VERSION 5.7 ;
BUSBITCHARS "[]" ;
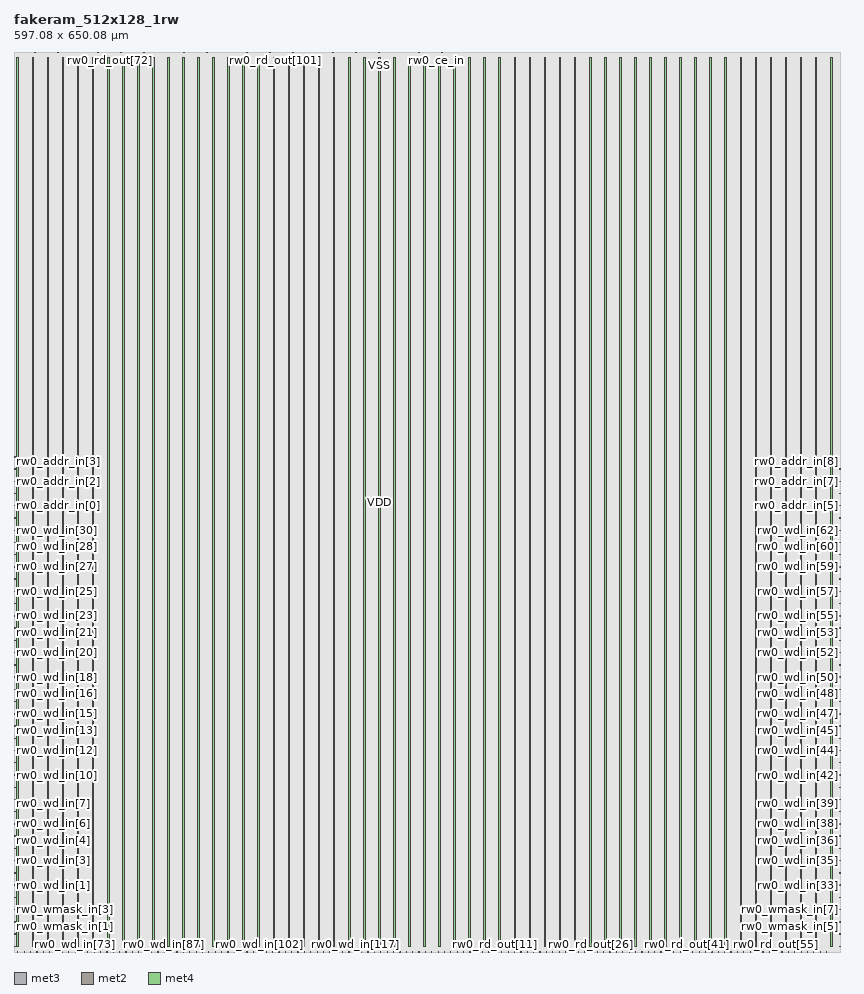
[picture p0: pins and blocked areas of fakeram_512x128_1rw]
MACRO fakeram_512x128_1rw
  FOREIGN fakeram_512x128_1rw 0 0 ;
  SYMMETRY X Y R90 ;
  SIZE 597.080 BY 650.080 ;
  CLASS BLOCK ;
  PIN rw0_wmask_in[0]
    DIRECTION INPUT ;
    USE SIGNAL ;
    SHAPE ABUTMENT ;
    PORT
      LAYER met3 ;
      RECT 0.000 3.930 0.900 4.230 ;
    END
  END rw0_wmask_in[0]
  PIN rw0_wmask_in[1]
    DIRECTION INPUT ;
    USE SIGNAL ;
    SHAPE ABUTMENT ;
    PORT
      LAYER met3 ;
      RECT 0.000 12.770 0.900 13.070 ;
    END
  END rw0_wmask_in[1]
  PIN rw0_wmask_in[2]
    DIRECTION INPUT ;
    USE SIGNAL ;
    SHAPE ABUTMENT ;
    PORT
      LAYER met3 ;
      RECT 0.000 21.610 0.900 21.910 ;
    END
  END rw0_wmask_in[2]
  PIN rw0_wmask_in[3]
    DIRECTION INPUT ;
    USE SIGNAL ;
    SHAPE ABUTMENT ;
    PORT
      LAYER met3 ;
      RECT 0.000 30.450 0.900 30.750 ;
    END
  END rw0_wmask_in[3]
  PIN rw0_wmask_in[4]
    DIRECTION INPUT ;
    USE SIGNAL ;
    SHAPE ABUTMENT ;
    PORT
      LAYER met3 ;
      RECT 596.180 3.930 597.080 4.230 ;
    END
  END rw0_wmask_in[4]
  PIN rw0_wmask_in[5]
    DIRECTION INPUT ;
    USE SIGNAL ;
    SHAPE ABUTMENT ;
    PORT
      LAYER met3 ;
      RECT 596.180 12.770 597.080 13.070 ;
    END
  END rw0_wmask_in[5]
  PIN rw0_wmask_in[6]
    DIRECTION INPUT ;
    USE SIGNAL ;
    SHAPE ABUTMENT ;
    PORT
      LAYER met3 ;
      RECT 596.180 21.610 597.080 21.910 ;
    END
  END rw0_wmask_in[6]
  PIN rw0_wmask_in[7]
    DIRECTION INPUT ;
    USE SIGNAL ;
    SHAPE ABUTMENT ;
    PORT
      LAYER met3 ;
      RECT 596.180 30.450 597.080 30.750 ;
    END
  END rw0_wmask_in[7]
  PIN rw0_wmask_in[8]
    DIRECTION INPUT ;
    USE SIGNAL ;
    SHAPE ABUTMENT ;
    PORT
      LAYER met2 ;
      RECT 2.690 649.660 2.830 650.080 ;
    END
  END rw0_wmask_in[8]
  PIN rw0_wmask_in[9]
    DIRECTION INPUT ;
    USE SIGNAL ;
    SHAPE ABUTMENT ;
    PORT
      LAYER met2 ;
      RECT 6.830 649.660 6.970 650.080 ;
    END
  END rw0_wmask_in[9]
  PIN rw0_wmask_in[10]
    DIRECTION INPUT ;
    USE SIGNAL ;
    SHAPE ABUTMENT ;
    PORT
      LAYER met2 ;
      RECT 10.970 649.660 11.110 650.080 ;
    END
  END rw0_wmask_in[10]
  PIN rw0_wmask_in[11]
    DIRECTION INPUT ;
    USE SIGNAL ;
    SHAPE ABUTMENT ;
    PORT
      LAYER met2 ;
      RECT 15.110 649.660 15.250 650.080 ;
    END
  END rw0_wmask_in[11]
  PIN rw0_wmask_in[12]
    DIRECTION INPUT ;
    USE SIGNAL ;
    SHAPE ABUTMENT ;
    PORT
      LAYER met2 ;
      RECT 19.250 649.660 19.390 650.080 ;
    END
  END rw0_wmask_in[12]
  PIN rw0_wmask_in[13]
    DIRECTION INPUT ;
    USE SIGNAL ;
    SHAPE ABUTMENT ;
    PORT
      LAYER met2 ;
      RECT 23.390 649.660 23.530 650.080 ;
    END
  END rw0_wmask_in[13]
  PIN rw0_wmask_in[14]
    DIRECTION INPUT ;
    USE SIGNAL ;
    SHAPE ABUTMENT ;
    PORT
      LAYER met2 ;
      RECT 27.530 649.660 27.670 650.080 ;
    END
  END rw0_wmask_in[14]
  PIN rw0_wmask_in[15]
    DIRECTION INPUT ;
    USE SIGNAL ;
    SHAPE ABUTMENT ;
    PORT
      LAYER met2 ;
      RECT 31.670 649.660 31.810 650.080 ;
    END
  END rw0_wmask_in[15]
  PIN rw0_wd_in[0]
    DIRECTION INPUT ;
    USE SIGNAL ;
    SHAPE ABUTMENT ;
    PORT
      LAYER met3 ;
      RECT 0.000 39.290 0.900 39.590 ;
    END
  END rw0_wd_in[0]
  PIN rw0_wd_in[1]
    DIRECTION INPUT ;
    USE SIGNAL ;
    SHAPE ABUTMENT ;
    PORT
      LAYER met3 ;
      RECT 0.000 48.130 0.900 48.430 ;
    END
  END rw0_wd_in[1]
  PIN rw0_wd_in[2]
    DIRECTION INPUT ;
    USE SIGNAL ;
    SHAPE ABUTMENT ;
    PORT
      LAYER met3 ;
      RECT 0.000 56.970 0.900 57.270 ;
    END
  END rw0_wd_in[2]
  PIN rw0_wd_in[3]
    DIRECTION INPUT ;
    USE SIGNAL ;
    SHAPE ABUTMENT ;
    PORT
      LAYER met3 ;
      RECT 0.000 65.810 0.900 66.110 ;
    END
  END rw0_wd_in[3]
  PIN rw0_wd_in[4]
    DIRECTION INPUT ;
    USE SIGNAL ;
    SHAPE ABUTMENT ;
    PORT
      LAYER met3 ;
      RECT 0.000 74.650 0.900 74.950 ;
    END
  END rw0_wd_in[4]
  PIN rw0_wd_in[5]
    DIRECTION INPUT ;
    USE SIGNAL ;
    SHAPE ABUTMENT ;
    PORT
      LAYER met3 ;
      RECT 0.000 83.490 0.900 83.790 ;
    END
  END rw0_wd_in[5]
  PIN rw0_wd_in[6]
    DIRECTION INPUT ;
    USE SIGNAL ;
    SHAPE ABUTMENT ;
    PORT
      LAYER met3 ;
      RECT 0.000 92.330 0.900 92.630 ;
    END
  END rw0_wd_in[6]
  PIN rw0_wd_in[7]
    DIRECTION INPUT ;
    USE SIGNAL ;
    SHAPE ABUTMENT ;
    PORT
      LAYER met3 ;
      RECT 0.000 101.170 0.900 101.470 ;
    END
  END rw0_wd_in[7]
  PIN rw0_wd_in[8]
    DIRECTION INPUT ;
    USE SIGNAL ;
    SHAPE ABUTMENT ;
    PORT
      LAYER met3 ;
      RECT 0.000 110.010 0.900 110.310 ;
    END
  END rw0_wd_in[8]
  PIN rw0_wd_in[9]
    DIRECTION INPUT ;
    USE SIGNAL ;
    SHAPE ABUTMENT ;
    PORT
      LAYER met3 ;
      RECT 0.000 118.850 0.900 119.150 ;
    END
  END rw0_wd_in[9]
  PIN rw0_wd_in[10]
    DIRECTION INPUT ;
    USE SIGNAL ;
    SHAPE ABUTMENT ;
    PORT
      LAYER met3 ;
      RECT 0.000 127.690 0.900 127.990 ;
    END
  END rw0_wd_in[10]
  PIN rw0_wd_in[11]
    DIRECTION INPUT ;
    USE SIGNAL ;
    SHAPE ABUTMENT ;
    PORT
      LAYER met3 ;
      RECT 0.000 136.530 0.900 136.830 ;
    END
  END rw0_wd_in[11]
  PIN rw0_wd_in[12]
    DIRECTION INPUT ;
    USE SIGNAL ;
    SHAPE ABUTMENT ;
    PORT
      LAYER met3 ;
      RECT 0.000 145.370 0.900 145.670 ;
    END
  END rw0_wd_in[12]
  PIN rw0_wd_in[13]
    DIRECTION INPUT ;
    USE SIGNAL ;
    SHAPE ABUTMENT ;
    PORT
      LAYER met3 ;
      RECT 0.000 154.210 0.900 154.510 ;
    END
  END rw0_wd_in[13]
  PIN rw0_wd_in[14]
    DIRECTION INPUT ;
    USE SIGNAL ;
    SHAPE ABUTMENT ;
    PORT
      LAYER met3 ;
      RECT 0.000 163.050 0.900 163.350 ;
    END
  END rw0_wd_in[14]
  PIN rw0_wd_in[15]
    DIRECTION INPUT ;
    USE SIGNAL ;
    SHAPE ABUTMENT ;
    PORT
      LAYER met3 ;
      RECT 0.000 171.890 0.900 172.190 ;
    END
  END rw0_wd_in[15]
  PIN rw0_wd_in[16]
    DIRECTION INPUT ;
    USE SIGNAL ;
    SHAPE ABUTMENT ;
    PORT
      LAYER met3 ;
      RECT 0.000 180.730 0.900 181.030 ;
    END
  END rw0_wd_in[16]
  PIN rw0_wd_in[17]
    DIRECTION INPUT ;
    USE SIGNAL ;
    SHAPE ABUTMENT ;
    PORT
      LAYER met3 ;
      RECT 0.000 189.570 0.900 189.870 ;
    END
  END rw0_wd_in[17]
  PIN rw0_wd_in[18]
    DIRECTION INPUT ;
    USE SIGNAL ;
    SHAPE ABUTMENT ;
    PORT
      LAYER met3 ;
      RECT 0.000 198.410 0.900 198.710 ;
    END
  END rw0_wd_in[18]
  PIN rw0_wd_in[19]
    DIRECTION INPUT ;
    USE SIGNAL ;
    SHAPE ABUTMENT ;
    PORT
      LAYER met3 ;
      RECT 0.000 207.250 0.900 207.550 ;
    END
  END rw0_wd_in[19]
  PIN rw0_wd_in[20]
    DIRECTION INPUT ;
    USE SIGNAL ;
    SHAPE ABUTMENT ;
    PORT
      LAYER met3 ;
      RECT 0.000 216.090 0.900 216.390 ;
    END
  END rw0_wd_in[20]
  PIN rw0_wd_in[21]
    DIRECTION INPUT ;
    USE SIGNAL ;
    SHAPE ABUTMENT ;
    PORT
      LAYER met3 ;
      RECT 0.000 224.930 0.900 225.230 ;
    END
  END rw0_wd_in[21]
  PIN rw0_wd_in[22]
    DIRECTION INPUT ;
    USE SIGNAL ;
    SHAPE ABUTMENT ;
    PORT
      LAYER met3 ;
      RECT 0.000 233.770 0.900 234.070 ;
    END
  END rw0_wd_in[22]
  PIN rw0_wd_in[23]
    DIRECTION INPUT ;
    USE SIGNAL ;
    SHAPE ABUTMENT ;
    PORT
      LAYER met3 ;
      RECT 0.000 242.610 0.900 242.910 ;
    END
  END rw0_wd_in[23]
  PIN rw0_wd_in[24]
    DIRECTION INPUT ;
    USE SIGNAL ;
    SHAPE ABUTMENT ;
    PORT
      LAYER met3 ;
      RECT 0.000 251.450 0.900 251.750 ;
    END
  END rw0_wd_in[24]
  PIN rw0_wd_in[25]
    DIRECTION INPUT ;
    USE SIGNAL ;
    SHAPE ABUTMENT ;
    PORT
      LAYER met3 ;
      RECT 0.000 260.290 0.900 260.590 ;
    END
  END rw0_wd_in[25]
  PIN rw0_wd_in[26]
    DIRECTION INPUT ;
    USE SIGNAL ;
    SHAPE ABUTMENT ;
    PORT
      LAYER met3 ;
      RECT 0.000 269.130 0.900 269.430 ;
    END
  END rw0_wd_in[26]
  PIN rw0_wd_in[27]
    DIRECTION INPUT ;
    USE SIGNAL ;
    SHAPE ABUTMENT ;
    PORT
      LAYER met3 ;
      RECT 0.000 277.970 0.900 278.270 ;
    END
  END rw0_wd_in[27]
  PIN rw0_wd_in[28]
    DIRECTION INPUT ;
    USE SIGNAL ;
    SHAPE ABUTMENT ;
    PORT
      LAYER met3 ;
      RECT 0.000 286.810 0.900 287.110 ;
    END
  END rw0_wd_in[28]
  PIN rw0_wd_in[29]
    DIRECTION INPUT ;
    USE SIGNAL ;
    SHAPE ABUTMENT ;
    PORT
      LAYER met3 ;
      RECT 0.000 295.650 0.900 295.950 ;
    END
  END rw0_wd_in[29]
  PIN rw0_wd_in[30]
    DIRECTION INPUT ;
    USE SIGNAL ;
    SHAPE ABUTMENT ;
    PORT
      LAYER met3 ;
      RECT 0.000 304.490 0.900 304.790 ;
    END
  END rw0_wd_in[30]
  PIN rw0_wd_in[31]
    DIRECTION INPUT ;
    USE SIGNAL ;
    SHAPE ABUTMENT ;
    PORT
      LAYER met3 ;
      RECT 0.000 313.330 0.900 313.630 ;
    END
  END rw0_wd_in[31]
  PIN rw0_wd_in[32]
    DIRECTION INPUT ;
    USE SIGNAL ;
    SHAPE ABUTMENT ;
    PORT
      LAYER met3 ;
      RECT 596.180 39.290 597.080 39.590 ;
    END
  END rw0_wd_in[32]
  PIN rw0_wd_in[33]
    DIRECTION INPUT ;
    USE SIGNAL ;
    SHAPE ABUTMENT ;
    PORT
      LAYER met3 ;
      RECT 596.180 48.130 597.080 48.430 ;
    END
  END rw0_wd_in[33]
  PIN rw0_wd_in[34]
    DIRECTION INPUT ;
    USE SIGNAL ;
    SHAPE ABUTMENT ;
    PORT
      LAYER met3 ;
      RECT 596.180 56.970 597.080 57.270 ;
    END
  END rw0_wd_in[34]
  PIN rw0_wd_in[35]
    DIRECTION INPUT ;
    USE SIGNAL ;
    SHAPE ABUTMENT ;
    PORT
      LAYER met3 ;
      RECT 596.180 65.810 597.080 66.110 ;
    END
  END rw0_wd_in[35]
  PIN rw0_wd_in[36]
    DIRECTION INPUT ;
    USE SIGNAL ;
    SHAPE ABUTMENT ;
    PORT
      LAYER met3 ;
      RECT 596.180 74.650 597.080 74.950 ;
    END
  END rw0_wd_in[36]
  PIN rw0_wd_in[37]
    DIRECTION INPUT ;
    USE SIGNAL ;
    SHAPE ABUTMENT ;
    PORT
      LAYER met3 ;
      RECT 596.180 83.490 597.080 83.790 ;
    END
  END rw0_wd_in[37]
  PIN rw0_wd_in[38]
    DIRECTION INPUT ;
    USE SIGNAL ;
    SHAPE ABUTMENT ;
    PORT
      LAYER met3 ;
      RECT 596.180 92.330 597.080 92.630 ;
    END
  END rw0_wd_in[38]
  PIN rw0_wd_in[39]
    DIRECTION INPUT ;
    USE SIGNAL ;
    SHAPE ABUTMENT ;
    PORT
      LAYER met3 ;
      RECT 596.180 101.170 597.080 101.470 ;
    END
  END rw0_wd_in[39]
  PIN rw0_wd_in[40]
    DIRECTION INPUT ;
    USE SIGNAL ;
    SHAPE ABUTMENT ;
    PORT
      LAYER met3 ;
      RECT 596.180 110.010 597.080 110.310 ;
    END
  END rw0_wd_in[40]
  PIN rw0_wd_in[41]
    DIRECTION INPUT ;
    USE SIGNAL ;
    SHAPE ABUTMENT ;
    PORT
      LAYER met3 ;
      RECT 596.180 118.850 597.080 119.150 ;
    END
  END rw0_wd_in[41]
  PIN rw0_wd_in[42]
    DIRECTION INPUT ;
    USE SIGNAL ;
    SHAPE ABUTMENT ;
    PORT
      LAYER met3 ;
      RECT 596.180 127.690 597.080 127.990 ;
    END
  END rw0_wd_in[42]
  PIN rw0_wd_in[43]
    DIRECTION INPUT ;
    USE SIGNAL ;
    SHAPE ABUTMENT ;
    PORT
      LAYER met3 ;
      RECT 596.180 136.530 597.080 136.830 ;
    END
  END rw0_wd_in[43]
  PIN rw0_wd_in[44]
    DIRECTION INPUT ;
    USE SIGNAL ;
    SHAPE ABUTMENT ;
    PORT
      LAYER met3 ;
      RECT 596.180 145.370 597.080 145.670 ;
    END
  END rw0_wd_in[44]
  PIN rw0_wd_in[45]
    DIRECTION INPUT ;
    USE SIGNAL ;
    SHAPE ABUTMENT ;
    PORT
      LAYER met3 ;
      RECT 596.180 154.210 597.080 154.510 ;
    END
  END rw0_wd_in[45]
  PIN rw0_wd_in[46]
    DIRECTION INPUT ;
    USE SIGNAL ;
    SHAPE ABUTMENT ;
    PORT
      LAYER met3 ;
      RECT 596.180 163.050 597.080 163.350 ;
    END
  END rw0_wd_in[46]
  PIN rw0_wd_in[47]
    DIRECTION INPUT ;
    USE SIGNAL ;
    SHAPE ABUTMENT ;
    PORT
      LAYER met3 ;
      RECT 596.180 171.890 597.080 172.190 ;
    END
  END rw0_wd_in[47]
  PIN rw0_wd_in[48]
    DIRECTION INPUT ;
    USE SIGNAL ;
    SHAPE ABUTMENT ;
    PORT
      LAYER met3 ;
      RECT 596.180 180.730 597.080 181.030 ;
    END
  END rw0_wd_in[48]
  PIN rw0_wd_in[49]
    DIRECTION INPUT ;
    USE SIGNAL ;
    SHAPE ABUTMENT ;
    PORT
      LAYER met3 ;
      RECT 596.180 189.570 597.080 189.870 ;
    END
  END rw0_wd_in[49]
  PIN rw0_wd_in[50]
    DIRECTION INPUT ;
    USE SIGNAL ;
    SHAPE ABUTMENT ;
    PORT
      LAYER met3 ;
      RECT 596.180 198.410 597.080 198.710 ;
    END
  END rw0_wd_in[50]
  PIN rw0_wd_in[51]
    DIRECTION INPUT ;
    USE SIGNAL ;
    SHAPE ABUTMENT ;
    PORT
      LAYER met3 ;
      RECT 596.180 207.250 597.080 207.550 ;
    END
  END rw0_wd_in[51]
  PIN rw0_wd_in[52]
    DIRECTION INPUT ;
    USE SIGNAL ;
    SHAPE ABUTMENT ;
    PORT
      LAYER met3 ;
      RECT 596.180 216.090 597.080 216.390 ;
    END
  END rw0_wd_in[52]
  PIN rw0_wd_in[53]
    DIRECTION INPUT ;
    USE SIGNAL ;
    SHAPE ABUTMENT ;
    PORT
      LAYER met3 ;
      RECT 596.180 224.930 597.080 225.230 ;
    END
  END rw0_wd_in[53]
  PIN rw0_wd_in[54]
    DIRECTION INPUT ;
    USE SIGNAL ;
    SHAPE ABUTMENT ;
    PORT
      LAYER met3 ;
      RECT 596.180 233.770 597.080 234.070 ;
    END
  END rw0_wd_in[54]
  PIN rw0_wd_in[55]
    DIRECTION INPUT ;
    USE SIGNAL ;
    SHAPE ABUTMENT ;
    PORT
      LAYER met3 ;
      RECT 596.180 242.610 597.080 242.910 ;
    END
  END rw0_wd_in[55]
  PIN rw0_wd_in[56]
    DIRECTION INPUT ;
    USE SIGNAL ;
    SHAPE ABUTMENT ;
    PORT
      LAYER met3 ;
      RECT 596.180 251.450 597.080 251.750 ;
    END
  END rw0_wd_in[56]
  PIN rw0_wd_in[57]
    DIRECTION INPUT ;
    USE SIGNAL ;
    SHAPE ABUTMENT ;
    PORT
      LAYER met3 ;
      RECT 596.180 260.290 597.080 260.590 ;
    END
  END rw0_wd_in[57]
  PIN rw0_wd_in[58]
    DIRECTION INPUT ;
    USE SIGNAL ;
    SHAPE ABUTMENT ;
    PORT
      LAYER met3 ;
      RECT 596.180 269.130 597.080 269.430 ;
    END
  END rw0_wd_in[58]
  PIN rw0_wd_in[59]
    DIRECTION INPUT ;
    USE SIGNAL ;
    SHAPE ABUTMENT ;
    PORT
      LAYER met3 ;
      RECT 596.180 277.970 597.080 278.270 ;
    END
  END rw0_wd_in[59]
  PIN rw0_wd_in[60]
    DIRECTION INPUT ;
    USE SIGNAL ;
    SHAPE ABUTMENT ;
    PORT
      LAYER met3 ;
      RECT 596.180 286.810 597.080 287.110 ;
    END
  END rw0_wd_in[60]
  PIN rw0_wd_in[61]
    DIRECTION INPUT ;
    USE SIGNAL ;
    SHAPE ABUTMENT ;
    PORT
      LAYER met3 ;
      RECT 596.180 295.650 597.080 295.950 ;
    END
  END rw0_wd_in[61]
  PIN rw0_wd_in[62]
    DIRECTION INPUT ;
    USE SIGNAL ;
    SHAPE ABUTMENT ;
    PORT
      LAYER met3 ;
      RECT 596.180 304.490 597.080 304.790 ;
    END
  END rw0_wd_in[62]
  PIN rw0_wd_in[63]
    DIRECTION INPUT ;
    USE SIGNAL ;
    SHAPE ABUTMENT ;
    PORT
      LAYER met3 ;
      RECT 596.180 313.330 597.080 313.630 ;
    END
  END rw0_wd_in[63]
  PIN rw0_wd_in[64]
    DIRECTION OUTPUT ;
    USE SIGNAL ;
    SHAPE ABUTMENT ;
    PORT
      LAYER met2 ;
      RECT 2.690 0.000 2.830 0.420 ;
    END
  END rw0_wd_in[64]
  PIN rw0_wd_in[65]
    DIRECTION OUTPUT ;
    USE SIGNAL ;
    SHAPE ABUTMENT ;
    PORT
      LAYER met2 ;
      RECT 7.290 0.000 7.430 0.420 ;
    END
  END rw0_wd_in[65]
  PIN rw0_wd_in[66]
    DIRECTION OUTPUT ;
    USE SIGNAL ;
    SHAPE ABUTMENT ;
    PORT
      LAYER met2 ;
      RECT 11.890 0.000 12.030 0.420 ;
    END
  END rw0_wd_in[66]
  PIN rw0_wd_in[67]
    DIRECTION OUTPUT ;
    USE SIGNAL ;
    SHAPE ABUTMENT ;
    PORT
      LAYER met2 ;
      RECT 16.490 0.000 16.630 0.420 ;
    END
  END rw0_wd_in[67]
  PIN rw0_wd_in[68]
    DIRECTION OUTPUT ;
    USE SIGNAL ;
    SHAPE ABUTMENT ;
    PORT
      LAYER met2 ;
      RECT 21.090 0.000 21.230 0.420 ;
    END
  END rw0_wd_in[68]
  PIN rw0_wd_in[69]
    DIRECTION OUTPUT ;
    USE SIGNAL ;
    SHAPE ABUTMENT ;
    PORT
      LAYER met2 ;
      RECT 25.690 0.000 25.830 0.420 ;
    END
  END rw0_wd_in[69]
  PIN rw0_wd_in[70]
    DIRECTION OUTPUT ;
    USE SIGNAL ;
    SHAPE ABUTMENT ;
    PORT
      LAYER met2 ;
      RECT 30.290 0.000 30.430 0.420 ;
    END
  END rw0_wd_in[70]
  PIN rw0_wd_in[71]
    DIRECTION OUTPUT ;
    USE SIGNAL ;
    SHAPE ABUTMENT ;
    PORT
      LAYER met2 ;
      RECT 34.890 0.000 35.030 0.420 ;
    END
  END rw0_wd_in[71]
  PIN rw0_wd_in[72]
    DIRECTION OUTPUT ;
    USE SIGNAL ;
    SHAPE ABUTMENT ;
    PORT
      LAYER met2 ;
      RECT 39.490 0.000 39.630 0.420 ;
    END
  END rw0_wd_in[72]
  PIN rw0_wd_in[73]
    DIRECTION OUTPUT ;
    USE SIGNAL ;
    SHAPE ABUTMENT ;
    PORT
      LAYER met2 ;
      RECT 44.090 0.000 44.230 0.420 ;
    END
  END rw0_wd_in[73]
  PIN rw0_wd_in[74]
    DIRECTION OUTPUT ;
    USE SIGNAL ;
    SHAPE ABUTMENT ;
    PORT
      LAYER met2 ;
      RECT 48.690 0.000 48.830 0.420 ;
    END
  END rw0_wd_in[74]
  PIN rw0_wd_in[75]
    DIRECTION OUTPUT ;
    USE SIGNAL ;
    SHAPE ABUTMENT ;
    PORT
      LAYER met2 ;
      RECT 53.290 0.000 53.430 0.420 ;
    END
  END rw0_wd_in[75]
  PIN rw0_wd_in[76]
    DIRECTION OUTPUT ;
    USE SIGNAL ;
    SHAPE ABUTMENT ;
    PORT
      LAYER met2 ;
      RECT 57.890 0.000 58.030 0.420 ;
    END
  END rw0_wd_in[76]
  PIN rw0_wd_in[77]
    DIRECTION OUTPUT ;
    USE SIGNAL ;
    SHAPE ABUTMENT ;
    PORT
      LAYER met2 ;
      RECT 62.490 0.000 62.630 0.420 ;
    END
  END rw0_wd_in[77]
  PIN rw0_wd_in[78]
    DIRECTION OUTPUT ;
    USE SIGNAL ;
    SHAPE ABUTMENT ;
    PORT
      LAYER met2 ;
      RECT 67.090 0.000 67.230 0.420 ;
    END
  END rw0_wd_in[78]
  PIN rw0_wd_in[79]
    DIRECTION OUTPUT ;
    USE SIGNAL ;
    SHAPE ABUTMENT ;
    PORT
      LAYER met2 ;
      RECT 71.690 0.000 71.830 0.420 ;
    END
  END rw0_wd_in[79]
  PIN rw0_wd_in[80]
    DIRECTION OUTPUT ;
    USE SIGNAL ;
    SHAPE ABUTMENT ;
    PORT
      LAYER met2 ;
      RECT 76.290 0.000 76.430 0.420 ;
    END
  END rw0_wd_in[80]
  PIN rw0_wd_in[81]
    DIRECTION OUTPUT ;
    USE SIGNAL ;
    SHAPE ABUTMENT ;
    PORT
      LAYER met2 ;
      RECT 80.890 0.000 81.030 0.420 ;
    END
  END rw0_wd_in[81]
  PIN rw0_wd_in[82]
    DIRECTION OUTPUT ;
    USE SIGNAL ;
    SHAPE ABUTMENT ;
    PORT
      LAYER met2 ;
      RECT 85.490 0.000 85.630 0.420 ;
    END
  END rw0_wd_in[82]
  PIN rw0_wd_in[83]
    DIRECTION OUTPUT ;
    USE SIGNAL ;
    SHAPE ABUTMENT ;
    PORT
      LAYER met2 ;
      RECT 90.090 0.000 90.230 0.420 ;
    END
  END rw0_wd_in[83]
  PIN rw0_wd_in[84]
    DIRECTION OUTPUT ;
    USE SIGNAL ;
    SHAPE ABUTMENT ;
    PORT
      LAYER met2 ;
      RECT 94.690 0.000 94.830 0.420 ;
    END
  END rw0_wd_in[84]
  PIN rw0_wd_in[85]
    DIRECTION OUTPUT ;
    USE SIGNAL ;
    SHAPE ABUTMENT ;
    PORT
      LAYER met2 ;
      RECT 99.290 0.000 99.430 0.420 ;
    END
  END rw0_wd_in[85]
  PIN rw0_wd_in[86]
    DIRECTION OUTPUT ;
    USE SIGNAL ;
    SHAPE ABUTMENT ;
    PORT
      LAYER met2 ;
      RECT 103.890 0.000 104.030 0.420 ;
    END
  END rw0_wd_in[86]
  PIN rw0_wd_in[87]
    DIRECTION OUTPUT ;
    USE SIGNAL ;
    SHAPE ABUTMENT ;
    PORT
      LAYER met2 ;
      RECT 108.490 0.000 108.630 0.420 ;
    END
  END rw0_wd_in[87]
  PIN rw0_wd_in[88]
    DIRECTION OUTPUT ;
    USE SIGNAL ;
    SHAPE ABUTMENT ;
    PORT
      LAYER met2 ;
      RECT 113.090 0.000 113.230 0.420 ;
    END
  END rw0_wd_in[88]
  PIN rw0_wd_in[89]
    DIRECTION OUTPUT ;
    USE SIGNAL ;
    SHAPE ABUTMENT ;
    PORT
      LAYER met2 ;
      RECT 117.690 0.000 117.830 0.420 ;
    END
  END rw0_wd_in[89]
  PIN rw0_wd_in[90]
    DIRECTION OUTPUT ;
    USE SIGNAL ;
    SHAPE ABUTMENT ;
    PORT
      LAYER met2 ;
      RECT 122.290 0.000 122.430 0.420 ;
    END
  END rw0_wd_in[90]
  PIN rw0_wd_in[91]
    DIRECTION OUTPUT ;
    USE SIGNAL ;
    SHAPE ABUTMENT ;
    PORT
      LAYER met2 ;
      RECT 126.890 0.000 127.030 0.420 ;
    END
  END rw0_wd_in[91]
  PIN rw0_wd_in[92]
    DIRECTION OUTPUT ;
    USE SIGNAL ;
    SHAPE ABUTMENT ;
    PORT
      LAYER met2 ;
      RECT 131.490 0.000 131.630 0.420 ;
    END
  END rw0_wd_in[92]
  PIN rw0_wd_in[93]
    DIRECTION OUTPUT ;
    USE SIGNAL ;
    SHAPE ABUTMENT ;
    PORT
      LAYER met2 ;
      RECT 136.090 0.000 136.230 0.420 ;
    END
  END rw0_wd_in[93]
  PIN rw0_wd_in[94]
    DIRECTION OUTPUT ;
    USE SIGNAL ;
    SHAPE ABUTMENT ;
    PORT
      LAYER met2 ;
      RECT 140.690 0.000 140.830 0.420 ;
    END
  END rw0_wd_in[94]
  PIN rw0_wd_in[95]
    DIRECTION OUTPUT ;
    USE SIGNAL ;
    SHAPE ABUTMENT ;
    PORT
      LAYER met2 ;
      RECT 145.290 0.000 145.430 0.420 ;
    END
  END rw0_wd_in[95]
  PIN rw0_wd_in[96]
    DIRECTION OUTPUT ;
    USE SIGNAL ;
    SHAPE ABUTMENT ;
    PORT
      LAYER met2 ;
      RECT 149.890 0.000 150.030 0.420 ;
    END
  END rw0_wd_in[96]
  PIN rw0_wd_in[97]
    DIRECTION OUTPUT ;
    USE SIGNAL ;
    SHAPE ABUTMENT ;
    PORT
      LAYER met2 ;
      RECT 154.490 0.000 154.630 0.420 ;
    END
  END rw0_wd_in[97]
  PIN rw0_wd_in[98]
    DIRECTION OUTPUT ;
    USE SIGNAL ;
    SHAPE ABUTMENT ;
    PORT
      LAYER met2 ;
      RECT 159.090 0.000 159.230 0.420 ;
    END
  END rw0_wd_in[98]
  PIN rw0_wd_in[99]
    DIRECTION OUTPUT ;
    USE SIGNAL ;
    SHAPE ABUTMENT ;
    PORT
      LAYER met2 ;
      RECT 163.690 0.000 163.830 0.420 ;
    END
  END rw0_wd_in[99]
  PIN rw0_wd_in[100]
    DIRECTION OUTPUT ;
    USE SIGNAL ;
    SHAPE ABUTMENT ;
    PORT
      LAYER met2 ;
      RECT 168.290 0.000 168.430 0.420 ;
    END
  END rw0_wd_in[100]
  PIN rw0_wd_in[101]
    DIRECTION OUTPUT ;
    USE SIGNAL ;
    SHAPE ABUTMENT ;
    PORT
      LAYER met2 ;
      RECT 172.890 0.000 173.030 0.420 ;
    END
  END rw0_wd_in[101]
  PIN rw0_wd_in[102]
    DIRECTION OUTPUT ;
    USE SIGNAL ;
    SHAPE ABUTMENT ;
    PORT
      LAYER met2 ;
      RECT 177.490 0.000 177.630 0.420 ;
    END
  END rw0_wd_in[102]
  PIN rw0_wd_in[103]
    DIRECTION OUTPUT ;
    USE SIGNAL ;
    SHAPE ABUTMENT ;
    PORT
      LAYER met2 ;
      RECT 182.090 0.000 182.230 0.420 ;
    END
  END rw0_wd_in[103]
  PIN rw0_wd_in[104]
    DIRECTION OUTPUT ;
    USE SIGNAL ;
    SHAPE ABUTMENT ;
    PORT
      LAYER met2 ;
      RECT 186.690 0.000 186.830 0.420 ;
    END
  END rw0_wd_in[104]
  PIN rw0_wd_in[105]
    DIRECTION OUTPUT ;
    USE SIGNAL ;
    SHAPE ABUTMENT ;
    PORT
      LAYER met2 ;
      RECT 191.290 0.000 191.430 0.420 ;
    END
  END rw0_wd_in[105]
  PIN rw0_wd_in[106]
    DIRECTION OUTPUT ;
    USE SIGNAL ;
    SHAPE ABUTMENT ;
    PORT
      LAYER met2 ;
      RECT 195.890 0.000 196.030 0.420 ;
    END
  END rw0_wd_in[106]
  PIN rw0_wd_in[107]
    DIRECTION OUTPUT ;
    USE SIGNAL ;
    SHAPE ABUTMENT ;
    PORT
      LAYER met2 ;
      RECT 200.490 0.000 200.630 0.420 ;
    END
  END rw0_wd_in[107]
  PIN rw0_wd_in[108]
    DIRECTION OUTPUT ;
    USE SIGNAL ;
    SHAPE ABUTMENT ;
    PORT
      LAYER met2 ;
      RECT 205.090 0.000 205.230 0.420 ;
    END
  END rw0_wd_in[108]
  PIN rw0_wd_in[109]
    DIRECTION OUTPUT ;
    USE SIGNAL ;
    SHAPE ABUTMENT ;
    PORT
      LAYER met2 ;
      RECT 209.690 0.000 209.830 0.420 ;
    END
  END rw0_wd_in[109]
  PIN rw0_wd_in[110]
    DIRECTION OUTPUT ;
    USE SIGNAL ;
    SHAPE ABUTMENT ;
    PORT
      LAYER met2 ;
      RECT 214.290 0.000 214.430 0.420 ;
    END
  END rw0_wd_in[110]
  PIN rw0_wd_in[111]
    DIRECTION OUTPUT ;
    USE SIGNAL ;
    SHAPE ABUTMENT ;
    PORT
      LAYER met2 ;
      RECT 218.890 0.000 219.030 0.420 ;
    END
  END rw0_wd_in[111]
  PIN rw0_wd_in[112]
    DIRECTION OUTPUT ;
    USE SIGNAL ;
    SHAPE ABUTMENT ;
    PORT
      LAYER met2 ;
      RECT 223.490 0.000 223.630 0.420 ;
    END
  END rw0_wd_in[112]
  PIN rw0_wd_in[113]
    DIRECTION OUTPUT ;
    USE SIGNAL ;
    SHAPE ABUTMENT ;
    PORT
      LAYER met2 ;
      RECT 228.090 0.000 228.230 0.420 ;
    END
  END rw0_wd_in[113]
  PIN rw0_wd_in[114]
    DIRECTION OUTPUT ;
    USE SIGNAL ;
    SHAPE ABUTMENT ;
    PORT
      LAYER met2 ;
      RECT 232.690 0.000 232.830 0.420 ;
    END
  END rw0_wd_in[114]
  PIN rw0_wd_in[115]
    DIRECTION OUTPUT ;
    USE SIGNAL ;
    SHAPE ABUTMENT ;
    PORT
      LAYER met2 ;
      RECT 237.290 0.000 237.430 0.420 ;
    END
  END rw0_wd_in[115]
  PIN rw0_wd_in[116]
    DIRECTION OUTPUT ;
    USE SIGNAL ;
    SHAPE ABUTMENT ;
    PORT
      LAYER met2 ;
      RECT 241.890 0.000 242.030 0.420 ;
    END
  END rw0_wd_in[116]
  PIN rw0_wd_in[117]
    DIRECTION OUTPUT ;
    USE SIGNAL ;
    SHAPE ABUTMENT ;
    PORT
      LAYER met2 ;
      RECT 246.490 0.000 246.630 0.420 ;
    END
  END rw0_wd_in[117]
  PIN rw0_wd_in[118]
    DIRECTION OUTPUT ;
    USE SIGNAL ;
    SHAPE ABUTMENT ;
    PORT
      LAYER met2 ;
      RECT 251.090 0.000 251.230 0.420 ;
    END
  END rw0_wd_in[118]
  PIN rw0_wd_in[119]
    DIRECTION OUTPUT ;
    USE SIGNAL ;
    SHAPE ABUTMENT ;
    PORT
      LAYER met2 ;
      RECT 255.690 0.000 255.830 0.420 ;
    END
  END rw0_wd_in[119]
  PIN rw0_wd_in[120]
    DIRECTION OUTPUT ;
    USE SIGNAL ;
    SHAPE ABUTMENT ;
    PORT
      LAYER met2 ;
      RECT 260.290 0.000 260.430 0.420 ;
    END
  END rw0_wd_in[120]
  PIN rw0_wd_in[121]
    DIRECTION OUTPUT ;
    USE SIGNAL ;
    SHAPE ABUTMENT ;
    PORT
      LAYER met2 ;
      RECT 264.890 0.000 265.030 0.420 ;
    END
  END rw0_wd_in[121]
  PIN rw0_wd_in[122]
    DIRECTION OUTPUT ;
    USE SIGNAL ;
    SHAPE ABUTMENT ;
    PORT
      LAYER met2 ;
      RECT 269.490 0.000 269.630 0.420 ;
    END
  END rw0_wd_in[122]
  PIN rw0_wd_in[123]
    DIRECTION OUTPUT ;
    USE SIGNAL ;
    SHAPE ABUTMENT ;
    PORT
      LAYER met2 ;
      RECT 274.090 0.000 274.230 0.420 ;
    END
  END rw0_wd_in[123]
  PIN rw0_wd_in[124]
    DIRECTION OUTPUT ;
    USE SIGNAL ;
    SHAPE ABUTMENT ;
    PORT
      LAYER met2 ;
      RECT 278.690 0.000 278.830 0.420 ;
    END
  END rw0_wd_in[124]
  PIN rw0_wd_in[125]
    DIRECTION OUTPUT ;
    USE SIGNAL ;
    SHAPE ABUTMENT ;
    PORT
      LAYER met2 ;
      RECT 283.290 0.000 283.430 0.420 ;
    END
  END rw0_wd_in[125]
  PIN rw0_wd_in[126]
    DIRECTION OUTPUT ;
    USE SIGNAL ;
    SHAPE ABUTMENT ;
    PORT
      LAYER met2 ;
      RECT 287.890 0.000 288.030 0.420 ;
    END
  END rw0_wd_in[126]
  PIN rw0_wd_in[127]
    DIRECTION OUTPUT ;
    USE SIGNAL ;
    SHAPE ABUTMENT ;
    PORT
      LAYER met2 ;
      RECT 292.490 0.000 292.630 0.420 ;
    END
  END rw0_wd_in[127]
  PIN rw0_rd_out[0]
    DIRECTION OUTPUT ;
    USE SIGNAL ;
    SHAPE ABUTMENT ;
    PORT
      LAYER met2 ;
      RECT 297.090 0.000 297.230 0.420 ;
    END
  END rw0_rd_out[0]
  PIN rw0_rd_out[1]
    DIRECTION OUTPUT ;
    USE SIGNAL ;
    SHAPE ABUTMENT ;
    PORT
      LAYER met2 ;
      RECT 301.690 0.000 301.830 0.420 ;
    END
  END rw0_rd_out[1]
  PIN rw0_rd_out[2]
    DIRECTION OUTPUT ;
    USE SIGNAL ;
    SHAPE ABUTMENT ;
    PORT
      LAYER met2 ;
      RECT 306.290 0.000 306.430 0.420 ;
    END
  END rw0_rd_out[2]
  PIN rw0_rd_out[3]
    DIRECTION OUTPUT ;
    USE SIGNAL ;
    SHAPE ABUTMENT ;
    PORT
      LAYER met2 ;
      RECT 310.890 0.000 311.030 0.420 ;
    END
  END rw0_rd_out[3]
  PIN rw0_rd_out[4]
    DIRECTION OUTPUT ;
    USE SIGNAL ;
    SHAPE ABUTMENT ;
    PORT
      LAYER met2 ;
      RECT 315.490 0.000 315.630 0.420 ;
    END
  END rw0_rd_out[4]
  PIN rw0_rd_out[5]
    DIRECTION OUTPUT ;
    USE SIGNAL ;
    SHAPE ABUTMENT ;
    PORT
      LAYER met2 ;
      RECT 320.090 0.000 320.230 0.420 ;
    END
  END rw0_rd_out[5]
  PIN rw0_rd_out[6]
    DIRECTION OUTPUT ;
    USE SIGNAL ;
    SHAPE ABUTMENT ;
    PORT
      LAYER met2 ;
      RECT 324.690 0.000 324.830 0.420 ;
    END
  END rw0_rd_out[6]
  PIN rw0_rd_out[7]
    DIRECTION OUTPUT ;
    USE SIGNAL ;
    SHAPE ABUTMENT ;
    PORT
      LAYER met2 ;
      RECT 329.290 0.000 329.430 0.420 ;
    END
  END rw0_rd_out[7]
  PIN rw0_rd_out[8]
    DIRECTION OUTPUT ;
    USE SIGNAL ;
    SHAPE ABUTMENT ;
    PORT
      LAYER met2 ;
      RECT 333.890 0.000 334.030 0.420 ;
    END
  END rw0_rd_out[8]
  PIN rw0_rd_out[9]
    DIRECTION OUTPUT ;
    USE SIGNAL ;
    SHAPE ABUTMENT ;
    PORT
      LAYER met2 ;
      RECT 338.490 0.000 338.630 0.420 ;
    END
  END rw0_rd_out[9]
  PIN rw0_rd_out[10]
    DIRECTION OUTPUT ;
    USE SIGNAL ;
    SHAPE ABUTMENT ;
    PORT
      LAYER met2 ;
      RECT 343.090 0.000 343.230 0.420 ;
    END
  END rw0_rd_out[10]
  PIN rw0_rd_out[11]
    DIRECTION OUTPUT ;
    USE SIGNAL ;
    SHAPE ABUTMENT ;
    PORT
      LAYER met2 ;
      RECT 347.690 0.000 347.830 0.420 ;
    END
  END rw0_rd_out[11]
  PIN rw0_rd_out[12]
    DIRECTION OUTPUT ;
    USE SIGNAL ;
    SHAPE ABUTMENT ;
    PORT
      LAYER met2 ;
      RECT 352.290 0.000 352.430 0.420 ;
    END
  END rw0_rd_out[12]
  PIN rw0_rd_out[13]
    DIRECTION OUTPUT ;
    USE SIGNAL ;
    SHAPE ABUTMENT ;
    PORT
      LAYER met2 ;
      RECT 356.890 0.000 357.030 0.420 ;
    END
  END rw0_rd_out[13]
  PIN rw0_rd_out[14]
    DIRECTION OUTPUT ;
    USE SIGNAL ;
    SHAPE ABUTMENT ;
    PORT
      LAYER met2 ;
      RECT 361.490 0.000 361.630 0.420 ;
    END
  END rw0_rd_out[14]
  PIN rw0_rd_out[15]
    DIRECTION OUTPUT ;
    USE SIGNAL ;
    SHAPE ABUTMENT ;
    PORT
      LAYER met2 ;
      RECT 366.090 0.000 366.230 0.420 ;
    END
  END rw0_rd_out[15]
  PIN rw0_rd_out[16]
    DIRECTION OUTPUT ;
    USE SIGNAL ;
    SHAPE ABUTMENT ;
    PORT
      LAYER met2 ;
      RECT 370.690 0.000 370.830 0.420 ;
    END
  END rw0_rd_out[16]
  PIN rw0_rd_out[17]
    DIRECTION OUTPUT ;
    USE SIGNAL ;
    SHAPE ABUTMENT ;
    PORT
      LAYER met2 ;
      RECT 375.290 0.000 375.430 0.420 ;
    END
  END rw0_rd_out[17]
  PIN rw0_rd_out[18]
    DIRECTION OUTPUT ;
    USE SIGNAL ;
    SHAPE ABUTMENT ;
    PORT
      LAYER met2 ;
      RECT 379.890 0.000 380.030 0.420 ;
    END
  END rw0_rd_out[18]
  PIN rw0_rd_out[19]
    DIRECTION OUTPUT ;
    USE SIGNAL ;
    SHAPE ABUTMENT ;
    PORT
      LAYER met2 ;
      RECT 384.490 0.000 384.630 0.420 ;
    END
  END rw0_rd_out[19]
  PIN rw0_rd_out[20]
    DIRECTION OUTPUT ;
    USE SIGNAL ;
    SHAPE ABUTMENT ;
    PORT
      LAYER met2 ;
      RECT 389.090 0.000 389.230 0.420 ;
    END
  END rw0_rd_out[20]
  PIN rw0_rd_out[21]
    DIRECTION OUTPUT ;
    USE SIGNAL ;
    SHAPE ABUTMENT ;
    PORT
      LAYER met2 ;
      RECT 393.690 0.000 393.830 0.420 ;
    END
  END rw0_rd_out[21]
  PIN rw0_rd_out[22]
    DIRECTION OUTPUT ;
    USE SIGNAL ;
    SHAPE ABUTMENT ;
    PORT
      LAYER met2 ;
      RECT 398.290 0.000 398.430 0.420 ;
    END
  END rw0_rd_out[22]
  PIN rw0_rd_out[23]
    DIRECTION OUTPUT ;
    USE SIGNAL ;
    SHAPE ABUTMENT ;
    PORT
      LAYER met2 ;
      RECT 402.890 0.000 403.030 0.420 ;
    END
  END rw0_rd_out[23]
  PIN rw0_rd_out[24]
    DIRECTION OUTPUT ;
    USE SIGNAL ;
    SHAPE ABUTMENT ;
    PORT
      LAYER met2 ;
      RECT 407.490 0.000 407.630 0.420 ;
    END
  END rw0_rd_out[24]
  PIN rw0_rd_out[25]
    DIRECTION OUTPUT ;
    USE SIGNAL ;
    SHAPE ABUTMENT ;
    PORT
      LAYER met2 ;
      RECT 412.090 0.000 412.230 0.420 ;
    END
  END rw0_rd_out[25]
  PIN rw0_rd_out[26]
    DIRECTION OUTPUT ;
    USE SIGNAL ;
    SHAPE ABUTMENT ;
    PORT
      LAYER met2 ;
      RECT 416.690 0.000 416.830 0.420 ;
    END
  END rw0_rd_out[26]
  PIN rw0_rd_out[27]
    DIRECTION OUTPUT ;
    USE SIGNAL ;
    SHAPE ABUTMENT ;
    PORT
      LAYER met2 ;
      RECT 421.290 0.000 421.430 0.420 ;
    END
  END rw0_rd_out[27]
  PIN rw0_rd_out[28]
    DIRECTION OUTPUT ;
    USE SIGNAL ;
    SHAPE ABUTMENT ;
    PORT
      LAYER met2 ;
      RECT 425.890 0.000 426.030 0.420 ;
    END
  END rw0_rd_out[28]
  PIN rw0_rd_out[29]
    DIRECTION OUTPUT ;
    USE SIGNAL ;
    SHAPE ABUTMENT ;
    PORT
      LAYER met2 ;
      RECT 430.490 0.000 430.630 0.420 ;
    END
  END rw0_rd_out[29]
  PIN rw0_rd_out[30]
    DIRECTION OUTPUT ;
    USE SIGNAL ;
    SHAPE ABUTMENT ;
    PORT
      LAYER met2 ;
      RECT 435.090 0.000 435.230 0.420 ;
    END
  END rw0_rd_out[30]
  PIN rw0_rd_out[31]
    DIRECTION OUTPUT ;
    USE SIGNAL ;
    SHAPE ABUTMENT ;
    PORT
      LAYER met2 ;
      RECT 439.690 0.000 439.830 0.420 ;
    END
  END rw0_rd_out[31]
  PIN rw0_rd_out[32]
    DIRECTION OUTPUT ;
    USE SIGNAL ;
    SHAPE ABUTMENT ;
    PORT
      LAYER met2 ;
      RECT 444.290 0.000 444.430 0.420 ;
    END
  END rw0_rd_out[32]
  PIN rw0_rd_out[33]
    DIRECTION OUTPUT ;
    USE SIGNAL ;
    SHAPE ABUTMENT ;
    PORT
      LAYER met2 ;
      RECT 448.890 0.000 449.030 0.420 ;
    END
  END rw0_rd_out[33]
  PIN rw0_rd_out[34]
    DIRECTION OUTPUT ;
    USE SIGNAL ;
    SHAPE ABUTMENT ;
    PORT
      LAYER met2 ;
      RECT 453.490 0.000 453.630 0.420 ;
    END
  END rw0_rd_out[34]
  PIN rw0_rd_out[35]
    DIRECTION OUTPUT ;
    USE SIGNAL ;
    SHAPE ABUTMENT ;
    PORT
      LAYER met2 ;
      RECT 458.090 0.000 458.230 0.420 ;
    END
  END rw0_rd_out[35]
  PIN rw0_rd_out[36]
    DIRECTION OUTPUT ;
    USE SIGNAL ;
    SHAPE ABUTMENT ;
    PORT
      LAYER met2 ;
      RECT 462.690 0.000 462.830 0.420 ;
    END
  END rw0_rd_out[36]
  PIN rw0_rd_out[37]
    DIRECTION OUTPUT ;
    USE SIGNAL ;
    SHAPE ABUTMENT ;
    PORT
      LAYER met2 ;
      RECT 467.290 0.000 467.430 0.420 ;
    END
  END rw0_rd_out[37]
  PIN rw0_rd_out[38]
    DIRECTION OUTPUT ;
    USE SIGNAL ;
    SHAPE ABUTMENT ;
    PORT
      LAYER met2 ;
      RECT 471.890 0.000 472.030 0.420 ;
    END
  END rw0_rd_out[38]
  PIN rw0_rd_out[39]
    DIRECTION OUTPUT ;
    USE SIGNAL ;
    SHAPE ABUTMENT ;
    PORT
      LAYER met2 ;
      RECT 476.490 0.000 476.630 0.420 ;
    END
  END rw0_rd_out[39]
  PIN rw0_rd_out[40]
    DIRECTION OUTPUT ;
    USE SIGNAL ;
    SHAPE ABUTMENT ;
    PORT
      LAYER met2 ;
      RECT 481.090 0.000 481.230 0.420 ;
    END
  END rw0_rd_out[40]
  PIN rw0_rd_out[41]
    DIRECTION OUTPUT ;
    USE SIGNAL ;
    SHAPE ABUTMENT ;
    PORT
      LAYER met2 ;
      RECT 485.690 0.000 485.830 0.420 ;
    END
  END rw0_rd_out[41]
  PIN rw0_rd_out[42]
    DIRECTION OUTPUT ;
    USE SIGNAL ;
    SHAPE ABUTMENT ;
    PORT
      LAYER met2 ;
      RECT 490.290 0.000 490.430 0.420 ;
    END
  END rw0_rd_out[42]
  PIN rw0_rd_out[43]
    DIRECTION OUTPUT ;
    USE SIGNAL ;
    SHAPE ABUTMENT ;
    PORT
      LAYER met2 ;
      RECT 494.890 0.000 495.030 0.420 ;
    END
  END rw0_rd_out[43]
  PIN rw0_rd_out[44]
    DIRECTION OUTPUT ;
    USE SIGNAL ;
    SHAPE ABUTMENT ;
    PORT
      LAYER met2 ;
      RECT 499.490 0.000 499.630 0.420 ;
    END
  END rw0_rd_out[44]
  PIN rw0_rd_out[45]
    DIRECTION OUTPUT ;
    USE SIGNAL ;
    SHAPE ABUTMENT ;
    PORT
      LAYER met2 ;
      RECT 504.090 0.000 504.230 0.420 ;
    END
  END rw0_rd_out[45]
  PIN rw0_rd_out[46]
    DIRECTION OUTPUT ;
    USE SIGNAL ;
    SHAPE ABUTMENT ;
    PORT
      LAYER met2 ;
      RECT 508.690 0.000 508.830 0.420 ;
    END
  END rw0_rd_out[46]
  PIN rw0_rd_out[47]
    DIRECTION OUTPUT ;
    USE SIGNAL ;
    SHAPE ABUTMENT ;
    PORT
      LAYER met2 ;
      RECT 513.290 0.000 513.430 0.420 ;
    END
  END rw0_rd_out[47]
  PIN rw0_rd_out[48]
    DIRECTION OUTPUT ;
    USE SIGNAL ;
    SHAPE ABUTMENT ;
    PORT
      LAYER met2 ;
      RECT 517.890 0.000 518.030 0.420 ;
    END
  END rw0_rd_out[48]
  PIN rw0_rd_out[49]
    DIRECTION OUTPUT ;
    USE SIGNAL ;
    SHAPE ABUTMENT ;
    PORT
      LAYER met2 ;
      RECT 522.490 0.000 522.630 0.420 ;
    END
  END rw0_rd_out[49]
  PIN rw0_rd_out[50]
    DIRECTION OUTPUT ;
    USE SIGNAL ;
    SHAPE ABUTMENT ;
    PORT
      LAYER met2 ;
      RECT 527.090 0.000 527.230 0.420 ;
    END
  END rw0_rd_out[50]
  PIN rw0_rd_out[51]
    DIRECTION OUTPUT ;
    USE SIGNAL ;
    SHAPE ABUTMENT ;
    PORT
      LAYER met2 ;
      RECT 531.690 0.000 531.830 0.420 ;
    END
  END rw0_rd_out[51]
  PIN rw0_rd_out[52]
    DIRECTION OUTPUT ;
    USE SIGNAL ;
    SHAPE ABUTMENT ;
    PORT
      LAYER met2 ;
      RECT 536.290 0.000 536.430 0.420 ;
    END
  END rw0_rd_out[52]
  PIN rw0_rd_out[53]
    DIRECTION OUTPUT ;
    USE SIGNAL ;
    SHAPE ABUTMENT ;
    PORT
      LAYER met2 ;
      RECT 540.890 0.000 541.030 0.420 ;
    END
  END rw0_rd_out[53]
  PIN rw0_rd_out[54]
    DIRECTION OUTPUT ;
    USE SIGNAL ;
    SHAPE ABUTMENT ;
    PORT
      LAYER met2 ;
      RECT 545.490 0.000 545.630 0.420 ;
    END
  END rw0_rd_out[54]
  PIN rw0_rd_out[55]
    DIRECTION OUTPUT ;
    USE SIGNAL ;
    SHAPE ABUTMENT ;
    PORT
      LAYER met2 ;
      RECT 550.090 0.000 550.230 0.420 ;
    END
  END rw0_rd_out[55]
  PIN rw0_rd_out[56]
    DIRECTION OUTPUT ;
    USE SIGNAL ;
    SHAPE ABUTMENT ;
    PORT
      LAYER met2 ;
      RECT 554.690 0.000 554.830 0.420 ;
    END
  END rw0_rd_out[56]
  PIN rw0_rd_out[57]
    DIRECTION OUTPUT ;
    USE SIGNAL ;
    SHAPE ABUTMENT ;
    PORT
      LAYER met2 ;
      RECT 559.290 0.000 559.430 0.420 ;
    END
  END rw0_rd_out[57]
  PIN rw0_rd_out[58]
    DIRECTION OUTPUT ;
    USE SIGNAL ;
    SHAPE ABUTMENT ;
    PORT
      LAYER met2 ;
      RECT 563.890 0.000 564.030 0.420 ;
    END
  END rw0_rd_out[58]
  PIN rw0_rd_out[59]
    DIRECTION OUTPUT ;
    USE SIGNAL ;
    SHAPE ABUTMENT ;
    PORT
      LAYER met2 ;
      RECT 568.490 0.000 568.630 0.420 ;
    END
  END rw0_rd_out[59]
  PIN rw0_rd_out[60]
    DIRECTION OUTPUT ;
    USE SIGNAL ;
    SHAPE ABUTMENT ;
    PORT
      LAYER met2 ;
      RECT 573.090 0.000 573.230 0.420 ;
    END
  END rw0_rd_out[60]
  PIN rw0_rd_out[61]
    DIRECTION OUTPUT ;
    USE SIGNAL ;
    SHAPE ABUTMENT ;
    PORT
      LAYER met2 ;
      RECT 577.690 0.000 577.830 0.420 ;
    END
  END rw0_rd_out[61]
  PIN rw0_rd_out[62]
    DIRECTION OUTPUT ;
    USE SIGNAL ;
    SHAPE ABUTMENT ;
    PORT
      LAYER met2 ;
      RECT 582.290 0.000 582.430 0.420 ;
    END
  END rw0_rd_out[62]
  PIN rw0_rd_out[63]
    DIRECTION OUTPUT ;
    USE SIGNAL ;
    SHAPE ABUTMENT ;
    PORT
      LAYER met2 ;
      RECT 586.890 0.000 587.030 0.420 ;
    END
  END rw0_rd_out[63]
  PIN rw0_rd_out[64]
    DIRECTION OUTPUT ;
    USE SIGNAL ;
    SHAPE ABUTMENT ;
    PORT
      LAYER met2 ;
      RECT 35.810 649.660 35.950 650.080 ;
    END
  END rw0_rd_out[64]
  PIN rw0_rd_out[65]
    DIRECTION OUTPUT ;
    USE SIGNAL ;
    SHAPE ABUTMENT ;
    PORT
      LAYER met2 ;
      RECT 39.950 649.660 40.090 650.080 ;
    END
  END rw0_rd_out[65]
  PIN rw0_rd_out[66]
    DIRECTION OUTPUT ;
    USE SIGNAL ;
    SHAPE ABUTMENT ;
    PORT
      LAYER met2 ;
      RECT 44.090 649.660 44.230 650.080 ;
    END
  END rw0_rd_out[66]
  PIN rw0_rd_out[67]
    DIRECTION OUTPUT ;
    USE SIGNAL ;
    SHAPE ABUTMENT ;
    PORT
      LAYER met2 ;
      RECT 48.230 649.660 48.370 650.080 ;
    END
  END rw0_rd_out[67]
  PIN rw0_rd_out[68]
    DIRECTION OUTPUT ;
    USE SIGNAL ;
    SHAPE ABUTMENT ;
    PORT
      LAYER met2 ;
      RECT 52.370 649.660 52.510 650.080 ;
    END
  END rw0_rd_out[68]
  PIN rw0_rd_out[69]
    DIRECTION OUTPUT ;
    USE SIGNAL ;
    SHAPE ABUTMENT ;
    PORT
      LAYER met2 ;
      RECT 56.510 649.660 56.650 650.080 ;
    END
  END rw0_rd_out[69]
  PIN rw0_rd_out[70]
    DIRECTION OUTPUT ;
    USE SIGNAL ;
    SHAPE ABUTMENT ;
    PORT
      LAYER met2 ;
      RECT 60.650 649.660 60.790 650.080 ;
    END
  END rw0_rd_out[70]
  PIN rw0_rd_out[71]
    DIRECTION OUTPUT ;
    USE SIGNAL ;
    SHAPE ABUTMENT ;
    PORT
      LAYER met2 ;
      RECT 64.790 649.660 64.930 650.080 ;
    END
  END rw0_rd_out[71]
  PIN rw0_rd_out[72]
    DIRECTION OUTPUT ;
    USE SIGNAL ;
    SHAPE ABUTMENT ;
    PORT
      LAYER met2 ;
      RECT 68.930 649.660 69.070 650.080 ;
    END
  END rw0_rd_out[72]
  PIN rw0_rd_out[73]
    DIRECTION OUTPUT ;
    USE SIGNAL ;
    SHAPE ABUTMENT ;
    PORT
      LAYER met2 ;
      RECT 73.070 649.660 73.210 650.080 ;
    END
  END rw0_rd_out[73]
  PIN rw0_rd_out[74]
    DIRECTION OUTPUT ;
    USE SIGNAL ;
    SHAPE ABUTMENT ;
    PORT
      LAYER met2 ;
      RECT 77.210 649.660 77.350 650.080 ;
    END
  END rw0_rd_out[74]
  PIN rw0_rd_out[75]
    DIRECTION OUTPUT ;
    USE SIGNAL ;
    SHAPE ABUTMENT ;
    PORT
      LAYER met2 ;
      RECT 81.350 649.660 81.490 650.080 ;
    END
  END rw0_rd_out[75]
  PIN rw0_rd_out[76]
    DIRECTION OUTPUT ;
    USE SIGNAL ;
    SHAPE ABUTMENT ;
    PORT
      LAYER met2 ;
      RECT 85.490 649.660 85.630 650.080 ;
    END
  END rw0_rd_out[76]
  PIN rw0_rd_out[77]
    DIRECTION OUTPUT ;
    USE SIGNAL ;
    SHAPE ABUTMENT ;
    PORT
      LAYER met2 ;
      RECT 89.630 649.660 89.770 650.080 ;
    END
  END rw0_rd_out[77]
  PIN rw0_rd_out[78]
    DIRECTION OUTPUT ;
    USE SIGNAL ;
    SHAPE ABUTMENT ;
    PORT
      LAYER met2 ;
      RECT 93.770 649.660 93.910 650.080 ;
    END
  END rw0_rd_out[78]
  PIN rw0_rd_out[79]
    DIRECTION OUTPUT ;
    USE SIGNAL ;
    SHAPE ABUTMENT ;
    PORT
      LAYER met2 ;
      RECT 97.910 649.660 98.050 650.080 ;
    END
  END rw0_rd_out[79]
  PIN rw0_rd_out[80]
    DIRECTION OUTPUT ;
    USE SIGNAL ;
    SHAPE ABUTMENT ;
    PORT
      LAYER met2 ;
      RECT 102.050 649.660 102.190 650.080 ;
    END
  END rw0_rd_out[80]
  PIN rw0_rd_out[81]
    DIRECTION OUTPUT ;
    USE SIGNAL ;
    SHAPE ABUTMENT ;
    PORT
      LAYER met2 ;
      RECT 106.190 649.660 106.330 650.080 ;
    END
  END rw0_rd_out[81]
  PIN rw0_rd_out[82]
    DIRECTION OUTPUT ;
    USE SIGNAL ;
    SHAPE ABUTMENT ;
    PORT
      LAYER met2 ;
      RECT 110.330 649.660 110.470 650.080 ;
    END
  END rw0_rd_out[82]
  PIN rw0_rd_out[83]
    DIRECTION OUTPUT ;
    USE SIGNAL ;
    SHAPE ABUTMENT ;
    PORT
      LAYER met2 ;
      RECT 114.470 649.660 114.610 650.080 ;
    END
  END rw0_rd_out[83]
  PIN rw0_rd_out[84]
    DIRECTION OUTPUT ;
    USE SIGNAL ;
    SHAPE ABUTMENT ;
    PORT
      LAYER met2 ;
      RECT 118.610 649.660 118.750 650.080 ;
    END
  END rw0_rd_out[84]
  PIN rw0_rd_out[85]
    DIRECTION OUTPUT ;
    USE SIGNAL ;
    SHAPE ABUTMENT ;
    PORT
      LAYER met2 ;
      RECT 122.750 649.660 122.890 650.080 ;
    END
  END rw0_rd_out[85]
  PIN rw0_rd_out[86]
    DIRECTION OUTPUT ;
    USE SIGNAL ;
    SHAPE ABUTMENT ;
    PORT
      LAYER met2 ;
      RECT 126.890 649.660 127.030 650.080 ;
    END
  END rw0_rd_out[86]
  PIN rw0_rd_out[87]
    DIRECTION OUTPUT ;
    USE SIGNAL ;
    SHAPE ABUTMENT ;
    PORT
      LAYER met2 ;
      RECT 131.030 649.660 131.170 650.080 ;
    END
  END rw0_rd_out[87]
  PIN rw0_rd_out[88]
    DIRECTION OUTPUT ;
    USE SIGNAL ;
    SHAPE ABUTMENT ;
    PORT
      LAYER met2 ;
      RECT 135.170 649.660 135.310 650.080 ;
    END
  END rw0_rd_out[88]
  PIN rw0_rd_out[89]
    DIRECTION OUTPUT ;
    USE SIGNAL ;
    SHAPE ABUTMENT ;
    PORT
      LAYER met2 ;
      RECT 139.310 649.660 139.450 650.080 ;
    END
  END rw0_rd_out[89]
  PIN rw0_rd_out[90]
    DIRECTION OUTPUT ;
    USE SIGNAL ;
    SHAPE ABUTMENT ;
    PORT
      LAYER met2 ;
      RECT 143.450 649.660 143.590 650.080 ;
    END
  END rw0_rd_out[90]
  PIN rw0_rd_out[91]
    DIRECTION OUTPUT ;
    USE SIGNAL ;
    SHAPE ABUTMENT ;
    PORT
      LAYER met2 ;
      RECT 147.590 649.660 147.730 650.080 ;
    END
  END rw0_rd_out[91]
  PIN rw0_rd_out[92]
    DIRECTION OUTPUT ;
    USE SIGNAL ;
    SHAPE ABUTMENT ;
    PORT
      LAYER met2 ;
      RECT 151.730 649.660 151.870 650.080 ;
    END
  END rw0_rd_out[92]
  PIN rw0_rd_out[93]
    DIRECTION OUTPUT ;
    USE SIGNAL ;
    SHAPE ABUTMENT ;
    PORT
      LAYER met2 ;
      RECT 155.870 649.660 156.010 650.080 ;
    END
  END rw0_rd_out[93]
  PIN rw0_rd_out[94]
    DIRECTION OUTPUT ;
    USE SIGNAL ;
    SHAPE ABUTMENT ;
    PORT
      LAYER met2 ;
      RECT 160.010 649.660 160.150 650.080 ;
    END
  END rw0_rd_out[94]
  PIN rw0_rd_out[95]
    DIRECTION OUTPUT ;
    USE SIGNAL ;
    SHAPE ABUTMENT ;
    PORT
      LAYER met2 ;
      RECT 164.150 649.660 164.290 650.080 ;
    END
  END rw0_rd_out[95]
  PIN rw0_rd_out[96]
    DIRECTION OUTPUT ;
    USE SIGNAL ;
    SHAPE ABUTMENT ;
    PORT
      LAYER met2 ;
      RECT 168.290 649.660 168.430 650.080 ;
    END
  END rw0_rd_out[96]
  PIN rw0_rd_out[97]
    DIRECTION OUTPUT ;
    USE SIGNAL ;
    SHAPE ABUTMENT ;
    PORT
      LAYER met2 ;
      RECT 172.430 649.660 172.570 650.080 ;
    END
  END rw0_rd_out[97]
  PIN rw0_rd_out[98]
    DIRECTION OUTPUT ;
    USE SIGNAL ;
    SHAPE ABUTMENT ;
    PORT
      LAYER met2 ;
      RECT 176.570 649.660 176.710 650.080 ;
    END
  END rw0_rd_out[98]
  PIN rw0_rd_out[99]
    DIRECTION OUTPUT ;
    USE SIGNAL ;
    SHAPE ABUTMENT ;
    PORT
      LAYER met2 ;
      RECT 180.710 649.660 180.850 650.080 ;
    END
  END rw0_rd_out[99]
  PIN rw0_rd_out[100]
    DIRECTION OUTPUT ;
    USE SIGNAL ;
    SHAPE ABUTMENT ;
    PORT
      LAYER met2 ;
      RECT 184.850 649.660 184.990 650.080 ;
    END
  END rw0_rd_out[100]
  PIN rw0_rd_out[101]
    DIRECTION OUTPUT ;
    USE SIGNAL ;
    SHAPE ABUTMENT ;
    PORT
      LAYER met2 ;
      RECT 188.990 649.660 189.130 650.080 ;
    END
  END rw0_rd_out[101]
  PIN rw0_rd_out[102]
    DIRECTION OUTPUT ;
    USE SIGNAL ;
    SHAPE ABUTMENT ;
    PORT
      LAYER met2 ;
      RECT 193.130 649.660 193.270 650.080 ;
    END
  END rw0_rd_out[102]
  PIN rw0_rd_out[103]
    DIRECTION OUTPUT ;
    USE SIGNAL ;
    SHAPE ABUTMENT ;
    PORT
      LAYER met2 ;
      RECT 197.270 649.660 197.410 650.080 ;
    END
  END rw0_rd_out[103]
  PIN rw0_rd_out[104]
    DIRECTION OUTPUT ;
    USE SIGNAL ;
    SHAPE ABUTMENT ;
    PORT
      LAYER met2 ;
      RECT 201.410 649.660 201.550 650.080 ;
    END
  END rw0_rd_out[104]
  PIN rw0_rd_out[105]
    DIRECTION OUTPUT ;
    USE SIGNAL ;
    SHAPE ABUTMENT ;
    PORT
      LAYER met2 ;
      RECT 205.550 649.660 205.690 650.080 ;
    END
  END rw0_rd_out[105]
  PIN rw0_rd_out[106]
    DIRECTION OUTPUT ;
    USE SIGNAL ;
    SHAPE ABUTMENT ;
    PORT
      LAYER met2 ;
      RECT 209.690 649.660 209.830 650.080 ;
    END
  END rw0_rd_out[106]
  PIN rw0_rd_out[107]
    DIRECTION OUTPUT ;
    USE SIGNAL ;
    SHAPE ABUTMENT ;
    PORT
      LAYER met2 ;
      RECT 213.830 649.660 213.970 650.080 ;
    END
  END rw0_rd_out[107]
  PIN rw0_rd_out[108]
    DIRECTION OUTPUT ;
    USE SIGNAL ;
    SHAPE ABUTMENT ;
    PORT
      LAYER met2 ;
      RECT 217.970 649.660 218.110 650.080 ;
    END
  END rw0_rd_out[108]
  PIN rw0_rd_out[109]
    DIRECTION OUTPUT ;
    USE SIGNAL ;
    SHAPE ABUTMENT ;
    PORT
      LAYER met2 ;
      RECT 222.110 649.660 222.250 650.080 ;
    END
  END rw0_rd_out[109]
  PIN rw0_rd_out[110]
    DIRECTION OUTPUT ;
    USE SIGNAL ;
    SHAPE ABUTMENT ;
    PORT
      LAYER met2 ;
      RECT 226.250 649.660 226.390 650.080 ;
    END
  END rw0_rd_out[110]
  PIN rw0_rd_out[111]
    DIRECTION OUTPUT ;
    USE SIGNAL ;
    SHAPE ABUTMENT ;
    PORT
      LAYER met2 ;
      RECT 230.390 649.660 230.530 650.080 ;
    END
  END rw0_rd_out[111]
  PIN rw0_rd_out[112]
    DIRECTION OUTPUT ;
    USE SIGNAL ;
    SHAPE ABUTMENT ;
    PORT
      LAYER met2 ;
      RECT 234.530 649.660 234.670 650.080 ;
    END
  END rw0_rd_out[112]
  PIN rw0_rd_out[113]
    DIRECTION OUTPUT ;
    USE SIGNAL ;
    SHAPE ABUTMENT ;
    PORT
      LAYER met2 ;
      RECT 238.670 649.660 238.810 650.080 ;
    END
  END rw0_rd_out[113]
  PIN rw0_rd_out[114]
    DIRECTION OUTPUT ;
    USE SIGNAL ;
    SHAPE ABUTMENT ;
    PORT
      LAYER met2 ;
      RECT 242.810 649.660 242.950 650.080 ;
    END
  END rw0_rd_out[114]
  PIN rw0_rd_out[115]
    DIRECTION OUTPUT ;
    USE SIGNAL ;
    SHAPE ABUTMENT ;
    PORT
      LAYER met2 ;
      RECT 246.950 649.660 247.090 650.080 ;
    END
  END rw0_rd_out[115]
  PIN rw0_rd_out[116]
    DIRECTION OUTPUT ;
    USE SIGNAL ;
    SHAPE ABUTMENT ;
    PORT
      LAYER met2 ;
      RECT 251.090 649.660 251.230 650.080 ;
    END
  END rw0_rd_out[116]
  PIN rw0_rd_out[117]
    DIRECTION OUTPUT ;
    USE SIGNAL ;
    SHAPE ABUTMENT ;
    PORT
      LAYER met2 ;
      RECT 255.230 649.660 255.370 650.080 ;
    END
  END rw0_rd_out[117]
  PIN rw0_rd_out[118]
    DIRECTION OUTPUT ;
    USE SIGNAL ;
    SHAPE ABUTMENT ;
    PORT
      LAYER met2 ;
      RECT 259.370 649.660 259.510 650.080 ;
    END
  END rw0_rd_out[118]
  PIN rw0_rd_out[119]
    DIRECTION OUTPUT ;
    USE SIGNAL ;
    SHAPE ABUTMENT ;
    PORT
      LAYER met2 ;
      RECT 263.510 649.660 263.650 650.080 ;
    END
  END rw0_rd_out[119]
  PIN rw0_rd_out[120]
    DIRECTION OUTPUT ;
    USE SIGNAL ;
    SHAPE ABUTMENT ;
    PORT
      LAYER met2 ;
      RECT 267.650 649.660 267.790 650.080 ;
    END
  END rw0_rd_out[120]
  PIN rw0_rd_out[121]
    DIRECTION OUTPUT ;
    USE SIGNAL ;
    SHAPE ABUTMENT ;
    PORT
      LAYER met2 ;
      RECT 271.790 649.660 271.930 650.080 ;
    END
  END rw0_rd_out[121]
  PIN rw0_rd_out[122]
    DIRECTION OUTPUT ;
    USE SIGNAL ;
    SHAPE ABUTMENT ;
    PORT
      LAYER met2 ;
      RECT 275.930 649.660 276.070 650.080 ;
    END
  END rw0_rd_out[122]
  PIN rw0_rd_out[123]
    DIRECTION OUTPUT ;
    USE SIGNAL ;
    SHAPE ABUTMENT ;
    PORT
      LAYER met2 ;
      RECT 280.070 649.660 280.210 650.080 ;
    END
  END rw0_rd_out[123]
  PIN rw0_rd_out[124]
    DIRECTION OUTPUT ;
    USE SIGNAL ;
    SHAPE ABUTMENT ;
    PORT
      LAYER met2 ;
      RECT 284.210 649.660 284.350 650.080 ;
    END
  END rw0_rd_out[124]
  PIN rw0_rd_out[125]
    DIRECTION OUTPUT ;
    USE SIGNAL ;
    SHAPE ABUTMENT ;
    PORT
      LAYER met2 ;
      RECT 288.350 649.660 288.490 650.080 ;
    END
  END rw0_rd_out[125]
  PIN rw0_rd_out[126]
    DIRECTION OUTPUT ;
    USE SIGNAL ;
    SHAPE ABUTMENT ;
    PORT
      LAYER met2 ;
      RECT 292.490 649.660 292.630 650.080 ;
    END
  END rw0_rd_out[126]
  PIN rw0_rd_out[127]
    DIRECTION OUTPUT ;
    USE SIGNAL ;
    SHAPE ABUTMENT ;
    PORT
      LAYER met2 ;
      RECT 296.630 649.660 296.770 650.080 ;
    END
  END rw0_rd_out[127]
  PIN rw0_addr_in[0]
    DIRECTION INPUT ;
    USE SIGNAL ;
    SHAPE ABUTMENT ;
    PORT
      LAYER met3 ;
      RECT 0.000 322.170 0.900 322.470 ;
    END
  END rw0_addr_in[0]
  PIN rw0_addr_in[1]
    DIRECTION INPUT ;
    USE SIGNAL ;
    SHAPE ABUTMENT ;
    PORT
      LAYER met3 ;
      RECT 0.000 331.010 0.900 331.310 ;
    END
  END rw0_addr_in[1]
  PIN rw0_addr_in[2]
    DIRECTION INPUT ;
    USE SIGNAL ;
    SHAPE ABUTMENT ;
    PORT
      LAYER met3 ;
      RECT 0.000 339.850 0.900 340.150 ;
    END
  END rw0_addr_in[2]
  PIN rw0_addr_in[3]
    DIRECTION INPUT ;
    USE SIGNAL ;
    SHAPE ABUTMENT ;
    PORT
      LAYER met3 ;
      RECT 0.000 348.690 0.900 348.990 ;
    END
  END rw0_addr_in[3]
  PIN rw0_addr_in[4]
    DIRECTION INPUT ;
    USE SIGNAL ;
    SHAPE ABUTMENT ;
    PORT
      LAYER met3 ;
      RECT 0.000 357.530 0.900 357.830 ;
    END
  END rw0_addr_in[4]
  PIN rw0_addr_in[5]
    DIRECTION INPUT ;
    USE SIGNAL ;
    SHAPE ABUTMENT ;
    PORT
      LAYER met3 ;
      RECT 596.180 322.170 597.080 322.470 ;
    END
  END rw0_addr_in[5]
  PIN rw0_addr_in[6]
    DIRECTION INPUT ;
    USE SIGNAL ;
    SHAPE ABUTMENT ;
    PORT
      LAYER met3 ;
      RECT 596.180 331.010 597.080 331.310 ;
    END
  END rw0_addr_in[6]
  PIN rw0_addr_in[7]
    DIRECTION INPUT ;
    USE SIGNAL ;
    SHAPE ABUTMENT ;
    PORT
      LAYER met3 ;
      RECT 596.180 339.850 597.080 340.150 ;
    END
  END rw0_addr_in[7]
  PIN rw0_addr_in[8]
    DIRECTION INPUT ;
    USE SIGNAL ;
    SHAPE ABUTMENT ;
    PORT
      LAYER met3 ;
      RECT 596.180 348.690 597.080 348.990 ;
    END
  END rw0_addr_in[8]
  PIN rw0_we_in
    DIRECTION INPUT ;
    USE SIGNAL ;
    SHAPE ABUTMENT ;
    PORT
      LAYER met2 ;
      RECT 300.770 649.660 300.910 650.080 ;
    END
  END rw0_we_in
  PIN rw0_ce_in
    DIRECTION INPUT ;
    USE SIGNAL ;
    SHAPE ABUTMENT ;
    PORT
      LAYER met2 ;
      RECT 304.910 649.660 305.050 650.080 ;
    END
  END rw0_ce_in
  PIN rw0_clk
    DIRECTION INPUT ;
    USE SIGNAL ;
    SHAPE ABUTMENT ;
    PORT
      LAYER met2 ;
      RECT 309.050 649.660 309.190 650.080 ;
    END
  END rw0_clk
  PIN VSS
    DIRECTION INOUT ;
    USE GROUND ;
    PORT
      LAYER met4 ;
      RECT 2.160 4.080 3.360 646.000 ;
      RECT 13.040 4.080 14.240 646.000 ;
      RECT 23.920 4.080 25.120 646.000 ;
      RECT 34.800 4.080 36.000 646.000 ;
      RECT 45.680 4.080 46.880 646.000 ;
      RECT 56.560 4.080 57.760 646.000 ;
      RECT 67.440 4.080 68.640 646.000 ;
      RECT 78.320 4.080 79.520 646.000 ;
      RECT 89.200 4.080 90.400 646.000 ;
      RECT 100.080 4.080 101.280 646.000 ;
      RECT 110.960 4.080 112.160 646.000 ;
      RECT 121.840 4.080 123.040 646.000 ;
      RECT 132.720 4.080 133.920 646.000 ;
      RECT 143.600 4.080 144.800 646.000 ;
      RECT 154.480 4.080 155.680 646.000 ;
      RECT 165.360 4.080 166.560 646.000 ;
      RECT 176.240 4.080 177.440 646.000 ;
      RECT 187.120 4.080 188.320 646.000 ;
      RECT 198.000 4.080 199.200 646.000 ;
      RECT 208.880 4.080 210.080 646.000 ;
      RECT 219.760 4.080 220.960 646.000 ;
      RECT 230.640 4.080 231.840 646.000 ;
      RECT 241.520 4.080 242.720 646.000 ;
      RECT 252.400 4.080 253.600 646.000 ;
      RECT 263.280 4.080 264.480 646.000 ;
      RECT 274.160 4.080 275.360 646.000 ;
      RECT 285.040 4.080 286.240 646.000 ;
      RECT 295.920 4.080 297.120 646.000 ;
      RECT 306.800 4.080 308.000 646.000 ;
      RECT 317.680 4.080 318.880 646.000 ;
      RECT 328.560 4.080 329.760 646.000 ;
      RECT 339.440 4.080 340.640 646.000 ;
      RECT 350.320 4.080 351.520 646.000 ;
      RECT 361.200 4.080 362.400 646.000 ;
      RECT 372.080 4.080 373.280 646.000 ;
      RECT 382.960 4.080 384.160 646.000 ;
      RECT 393.840 4.080 395.040 646.000 ;
      RECT 404.720 4.080 405.920 646.000 ;
      RECT 415.600 4.080 416.800 646.000 ;
      RECT 426.480 4.080 427.680 646.000 ;
      RECT 437.360 4.080 438.560 646.000 ;
      RECT 448.240 4.080 449.440 646.000 ;
      RECT 459.120 4.080 460.320 646.000 ;
      RECT 470.000 4.080 471.200 646.000 ;
      RECT 480.880 4.080 482.080 646.000 ;
      RECT 491.760 4.080 492.960 646.000 ;
      RECT 502.640 4.080 503.840 646.000 ;
      RECT 513.520 4.080 514.720 646.000 ;
      RECT 524.400 4.080 525.600 646.000 ;
      RECT 535.280 4.080 536.480 646.000 ;
      RECT 546.160 4.080 547.360 646.000 ;
      RECT 557.040 4.080 558.240 646.000 ;
      RECT 567.920 4.080 569.120 646.000 ;
      RECT 578.800 4.080 580.000 646.000 ;
      RECT 589.680 4.080 590.880 646.000 ;
    END
  END VSS
  PIN VDD
    DIRECTION INOUT ;
    USE POWER ;
    PORT
      LAYER met4 ;
      RECT 2.160 4.080 3.360 646.000 ;
      RECT 13.040 4.080 14.240 646.000 ;
      RECT 23.920 4.080 25.120 646.000 ;
      RECT 34.800 4.080 36.000 646.000 ;
      RECT 45.680 4.080 46.880 646.000 ;
      RECT 56.560 4.080 57.760 646.000 ;
      RECT 67.440 4.080 68.640 646.000 ;
      RECT 78.320 4.080 79.520 646.000 ;
      RECT 89.200 4.080 90.400 646.000 ;
      RECT 100.080 4.080 101.280 646.000 ;
      RECT 110.960 4.080 112.160 646.000 ;
      RECT 121.840 4.080 123.040 646.000 ;
      RECT 132.720 4.080 133.920 646.000 ;
      RECT 143.600 4.080 144.800 646.000 ;
      RECT 154.480 4.080 155.680 646.000 ;
      RECT 165.360 4.080 166.560 646.000 ;
      RECT 176.240 4.080 177.440 646.000 ;
      RECT 187.120 4.080 188.320 646.000 ;
      RECT 198.000 4.080 199.200 646.000 ;
      RECT 208.880 4.080 210.080 646.000 ;
      RECT 219.760 4.080 220.960 646.000 ;
      RECT 230.640 4.080 231.840 646.000 ;
      RECT 241.520 4.080 242.720 646.000 ;
      RECT 252.400 4.080 253.600 646.000 ;
      RECT 263.280 4.080 264.480 646.000 ;
      RECT 274.160 4.080 275.360 646.000 ;
      RECT 285.040 4.080 286.240 646.000 ;
      RECT 295.920 4.080 297.120 646.000 ;
      RECT 306.800 4.080 308.000 646.000 ;
      RECT 317.680 4.080 318.880 646.000 ;
      RECT 328.560 4.080 329.760 646.000 ;
      RECT 339.440 4.080 340.640 646.000 ;
      RECT 350.320 4.080 351.520 646.000 ;
      RECT 361.200 4.080 362.400 646.000 ;
      RECT 372.080 4.080 373.280 646.000 ;
      RECT 382.960 4.080 384.160 646.000 ;
      RECT 393.840 4.080 395.040 646.000 ;
      RECT 404.720 4.080 405.920 646.000 ;
      RECT 415.600 4.080 416.800 646.000 ;
      RECT 426.480 4.080 427.680 646.000 ;
      RECT 437.360 4.080 438.560 646.000 ;
      RECT 448.240 4.080 449.440 646.000 ;
      RECT 459.120 4.080 460.320 646.000 ;
      RECT 470.000 4.080 471.200 646.000 ;
      RECT 480.880 4.080 482.080 646.000 ;
      RECT 491.760 4.080 492.960 646.000 ;
      RECT 502.640 4.080 503.840 646.000 ;
      RECT 513.520 4.080 514.720 646.000 ;
      RECT 524.400 4.080 525.600 646.000 ;
      RECT 535.280 4.080 536.480 646.000 ;
      RECT 546.160 4.080 547.360 646.000 ;
      RECT 557.040 4.080 558.240 646.000 ;
      RECT 567.920 4.080 569.120 646.000 ;
      RECT 578.800 4.080 580.000 646.000 ;
      RECT 589.680 4.080 590.880 646.000 ;
    END
  END VDD
  OBS
    LAYER met1 ;
    RECT 0 0 597.080 650.080 ;
    LAYER met2 ;
    RECT 0 0 597.080 650.080 ;
    LAYER met3 ;
    RECT 0 0 597.080 650.080 ;
    LAYER met4 ;
    RECT 0 0 597.080 650.080 ;
  END
END fakeram_512x128_1rw

END LIBRARY
